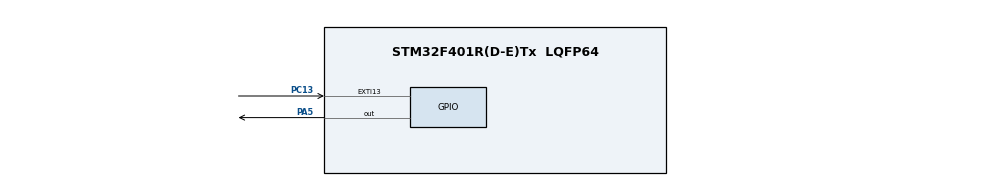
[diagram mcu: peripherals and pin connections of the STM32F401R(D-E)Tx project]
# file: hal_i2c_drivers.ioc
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Mcu.Family=STM32F4
Mcu.Name=STM32F401R(D-E)Tx
Mcu.Package=LQFP64
NVIC.EXTI15_10_IRQn=true\:0\:0\:false\:false\:true\:true\:true
NVIC.PriorityGroup=NVIC_PRIORITYGROUP_4
PA5.Signal=GPIO_Output
PC13-ANTI_TAMP.Signal=GPXTI13
ProjectManager.HeapSize=0x200
ProjectManager.StackSize=0x400
ProjectManager.TargetToolchain=STM32CubeIDE
RCC.48MHZClocksFreq_Value=84000000
RCC.AHBFreq_Value=84000000
RCC.APB1CLKDivider=RCC_HCLK_DIV2
RCC.APB1Freq_Value=42000000
RCC.APB1TimFreq_Value=84000000
RCC.APB2Freq_Value=84000000
RCC.APB2TimFreq_Value=84000000
RCC.CortexFreq_Value=84000000
RCC.HCLKFreq_Value=84000000
RCC.HSE_VALUE=25000000
RCC.HSI_VALUE=16000000
RCC.LSE_VALUE=32768
RCC.PLLM=10
RCC.PLLN=210
RCC.PLLP=RCC_PLLP_DIV4
RCC.SYSCLKFreq_VALUE=84000000
RCC.SYSCLKSource=RCC_SYSCLKSOURCE_PLLCLK
RCC.VCOOutputFreq_Value=336000000
board=custom

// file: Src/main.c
/* USER CODE BEGIN Header */
/**
  ******************************************************************************
  * @file           : main.c
  * @brief          : Main program body
  ******************************************************************************
  *
  ******************************************************************************
  */
/* USER CODE END Header */

#include "main.h"
#include "mcp9808.h"
//
static uint8_t txBuffer[1] = {MCP9808_REG_AMBIENT_TEMP_REG};
#define bytesToRead 6		// 3 data samples
static uint8_t rxBuffer[bytesToRead];
static uint8_t txSize = sizeof(txBuffer)/sizeof(txBuffer[0]);

void SystemClock_Config(void);
static void MX_GPIO_Init(void);
extern void initialise_monitor_handles(void);

I2C_Handle_t I2C1_handle;

/*
 * Initializing user-defined variables for I2C struct
 */
void I2C_Initilization()
{
	I2C1_handle.pI2Cx = I2C1;
	I2C1_handle.I2C_Config.I2C_AckControl = I2C_ACK_ENABLE;
	I2C1_handle.I2C_Config.I2C_SCLSpeed = I2C_SCL_SPEED_SM;
	I2C1_handle.I2C_Config.I2C_DeviceAddress = MCP9808_ADDR;
	I2C1_handle.I2C_Config.I2C_FMDutyCycle = I2C_FM_DUTY_2;
	I2C_Init(&I2C1_handle);
}

void GetTemperature(uint8_t interrupt)
{
	printf ("Reading %d bytes\n", bytesToRead);

	I2C1_handle.txBuffer = txBuffer;
	I2C1_handle.txBufferLength = txSize;
	I2C1_handle.pRxBuffer = rxBuffer;
	I2C1_handle.rxStartIndex = 0;
	I2C1_handle.rxBufferLength = BYTES_PER_TRANSACTION;
	I2C1_handle.rxBufferSize = bytesToRead;

	if (interrupt == SET)
	{
		ReadTemperatureInterrupt(&I2C1_handle);
	}
	else
	{
		ReadTemperature(&I2C1_handle, bytesToRead);
	}
}

int main(void)
{
	initialise_monitor_handles();
	printf ("Application is running...\n");

	HAL_Init();

  /* Configure the system clock */
	SystemClock_Config();

  /* Initialize all configured peripherals */
	MX_GPIO_Init();

  /* Initialize I2C struct */
    I2C_Initilization();

	/* read temperature from the sensor */
	GetTemperature(SET);			// interrupt
//	GetTemperature(RESET);			// polling approach

	while (1);

}

void SystemClock_Config(void)
{
  RCC_OscInitTypeDef RCC_OscInitStruct = {0};
  RCC_ClkInitTypeDef RCC_ClkInitStruct = {0};

  /** Configure the main internal regulator output voltage
  */
  __HAL_RCC_PWR_CLK_ENABLE();
  __HAL_PWR_VOLTAGESCALING_CONFIG(PWR_REGULATOR_VOLTAGE_SCALE2);
  /** Initializes the CPU, AHB and APB busses clocks
  */
  RCC_OscInitStruct.OscillatorType = RCC_OSCILLATORTYPE_HSI;
  RCC_OscInitStruct.HSIState = RCC_HSI_ON;
  RCC_OscInitStruct.HSICalibrationValue = RCC_HSICALIBRATION_DEFAULT;
  RCC_OscInitStruct.PLL.PLLState = RCC_PLL_NONE;
  if (HAL_RCC_OscConfig(&RCC_OscInitStruct) != HAL_OK)
  {
    Error_Handler();
  }
  /** Initializes the CPU, AHB and APB busses clocks
  */
  RCC_ClkInitStruct.ClockType = RCC_CLOCKTYPE_HCLK|RCC_CLOCKTYPE_SYSCLK
                              |RCC_CLOCKTYPE_PCLK1|RCC_CLOCKTYPE_PCLK2;
  RCC_ClkInitStruct.SYSCLKSource = RCC_SYSCLKSOURCE_HSI;
  RCC_ClkInitStruct.AHBCLKDivider = RCC_SYSCLK_DIV1;
  RCC_ClkInitStruct.APB1CLKDivider = RCC_HCLK_DIV1;
  RCC_ClkInitStruct.APB2CLKDivider = RCC_HCLK_DIV1;

  if (HAL_RCC_ClockConfig(&RCC_ClkInitStruct, FLASH_LATENCY_0) != HAL_OK)
  {
    Error_Handler();
  }
}

static void MX_GPIO_Init(void)
{
  GPIO_InitTypeDef GPIO_InitStruct = {0};

  /* GPIO Ports Clock Enable */
  __HAL_RCC_GPIOC_CLK_ENABLE();
  __HAL_RCC_GPIOA_CLK_ENABLE();
  __HAL_RCC_GPIOB_CLK_ENABLE();

  /* GPIO I2C Clock Enable */
//  __HAL_RCC_I2C1_CLK_ENABLE();

  /*Configure GPIO pin Output Level */
  HAL_GPIO_WritePin(GPIOA, GPIO_PIN_6, GPIO_PIN_RESET);

  /*Configure GPIO pin : PC13 */
  GPIO_InitStruct.Pin = GPIO_PIN_13;
  GPIO_InitStruct.Mode = GPIO_MODE_IT_RISING;
  GPIO_InitStruct.Pull = GPIO_NOPULL;
  HAL_GPIO_Init(GPIOC, &GPIO_InitStruct);

  /*Configure GPIO pin : PA5 */
  GPIO_InitStruct.Pin = GPIO_PIN_5;
  GPIO_InitStruct.Mode = GPIO_MODE_OUTPUT_PP;
  GPIO_InitStruct.Pull = GPIO_NOPULL;
  GPIO_InitStruct.Speed = GPIO_SPEED_FREQ_LOW;
  HAL_GPIO_Init(GPIOA, &GPIO_InitStruct);

  /* Configure I2C */
  GPIO_InitStruct.Mode = GPIO_MODE_AF_OD;
  GPIO_InitStruct.Pull = GPIO_NOPULL;
  GPIO_InitStruct.Speed = GPIO_SPEED_FREQ_HIGH;
  GPIO_InitStruct.Alternate = GPIO_AF4_I2C1;

  // scl
  GPIO_InitStruct.Pin = GPIO_PIN_6;
  HAL_GPIO_Init(GPIOB, &GPIO_InitStruct);

  // sdata
  GPIO_InitStruct.Pin = GPIO_PIN_7;
  HAL_GPIO_Init(GPIOB, &GPIO_InitStruct);

  /* EXTI GPIO init */
//  HAL_NVIC_SetPriority(EXTI15_10_IRQn, 0, 0);
//  HAL_NVIC_EnableIRQ(EXTI15_10_IRQn);

  /* EXTI I2C Interrupts */
  HAL_NVIC_EnableIRQ(I2C1_EV_IRQn);
  HAL_NVIC_EnableIRQ(I2C1_ER_IRQn);
}

void Error_Handler(void)
{
}

/************************ (C) COPYRIGHT STMicroelectronics *****END OF FILE****/
